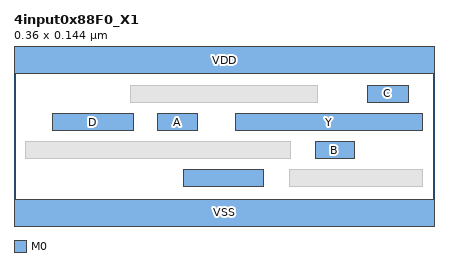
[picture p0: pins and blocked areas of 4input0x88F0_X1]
MACRO 4input0x88F0_X1
  CLASS CORE ;
  ORIGIN 0 0 ;
  FOREIGN 4input0x88F0_X1 0 0 ;
  SIZE 0.3600 BY 0.1440 ;
  SYMMETRY X Y ;
  SITE coresite ;
  PIN A
    DIRECTION INPUT ;
    USE SIGNAL ;
    PORT
      LAYER M0 ;
        RECT 0.1230 0.0770 0.1570 0.0910 ;
    END
  END A
  PIN B
    DIRECTION INPUT ;
    USE SIGNAL ;
    PORT
      LAYER M0 ;
        RECT 0.2580 0.0530 0.2920 0.0670 ;
    END
  END B
  PIN C
    DIRECTION INPUT ;
    USE SIGNAL ;
    PORT
      LAYER M0 ;
        RECT 0.3030 0.1010 0.3380 0.1150 ;
    END
  END C
  PIN D
    DIRECTION INPUT ;
    USE SIGNAL ;
    PORT
      LAYER M0 ;
        RECT 0.0330 0.0770 0.1020 0.0910 ;
    END
  END D
  PIN Y
    DIRECTION OUTPUT ;
    USE SIGNAL ;
    PORT
      LAYER M0 ;
        RECT 0.1900 0.0770 0.3500 0.0910 ;
        RECT 0.1450 0.0290 0.2140 0.0430 ;
    END
  END Y
  PIN VDD
    DIRECTION INOUT ;
    USE POWER ;
    SHAPE ABUTMENT ;
    PORT
      LAYER M0 ;
        RECT 0.0000 0.1260 0.3600 0.1620 ;
    END
  END VDD
  PIN VSS
    DIRECTION INOUT ;
    USE GROUND ;
    SHAPE ABUTMENT ;
    PORT
      LAYER M0 ;
        RECT 0.0000 -0.0180 0.3600 0.0180 ;
    END
  END VSS
  OBS
    LAYER M0 ;
      RECT 0.2360 0.0290 0.3500 0.0430 ;
      RECT 0.0100 0.0530 0.2370 0.0670 ;
      RECT 0.1000 0.1010 0.2600 0.1150 ;
  END
END 4input0x88F0_X1
